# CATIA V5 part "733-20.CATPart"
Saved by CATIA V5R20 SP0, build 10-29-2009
Part number: 733-20
Bounding box of the stored display mesh (mm): x -20 to 20, y -20 to 20, z -23 to 36
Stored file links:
  C:\Users\Utente\Desktop\IO LAVORO\3D X SITO CF\X SITO\733\733-20.CATPart

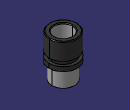
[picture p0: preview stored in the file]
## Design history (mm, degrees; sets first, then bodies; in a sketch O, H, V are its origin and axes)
Set1
  DatumSurface1 to DatumSurface25 "733-20"
Body1 (main body)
